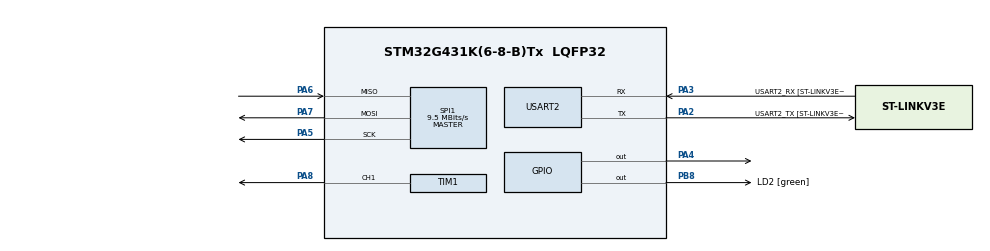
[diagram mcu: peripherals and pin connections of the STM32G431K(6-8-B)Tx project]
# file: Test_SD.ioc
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FATFS._MAX_SS=4096
FATFS._USE_LFN=1
Mcu.Family=STM32G4
Mcu.Name=STM32G431K(6-8-B)Tx
Mcu.Package=LQFP32
NVIC.PriorityGroup=NVIC_PRIORITYGROUP_4
PA13.GPIO_Label=T_SWDIO
PA13.Mode=Serial_Wire
PA13.Signal=SYS_JTMS-SWDIO
PA14.GPIO_Label=T_SWCLK
PA14.Mode=Serial_Wire
PA14.Signal=SYS_JTCK-SWCLK
PA2.GPIO_Label=USART2_TX [ST-LINKV3E_VCP_RX]
PA2.Mode=Asynchronous
PA2.Signal=USART2_TX
PA3.GPIO_Label=USART2_RX [ST-LINKV3E_VCP_TX]
PA3.Mode=Asynchronous
PA3.Signal=USART2_RX
PA4.Signal=GPIO_Output
PA5.Mode=Full_Duplex_Master
PA5.Signal=SPI1_SCK
PA6.Mode=Full_Duplex_Master
PA6.Signal=SPI1_MISO
PA7.Mode=Full_Duplex_Master
PA7.Signal=SPI1_MOSI
PA8.Signal=S_TIM1_CH1
PB3.GPIO_Label=T_SWO
PB3.Signal=SYS_JTDO-SWO
PB8-BOOT0.GPIO_Label=LD2 [green]
PB8-BOOT0.Signal=GPIO_Output
ProjectManager.HeapSize=0x200
ProjectManager.StackSize=0x400
ProjectManager.TargetToolchain=STM32CubeIDE
RCC.ADC12Freq_Value=152000000
RCC.AHBFreq_Value=152000000
RCC.APB1Freq_Value=152000000
RCC.APB1TimFreq_Value=152000000
RCC.APB2Freq_Value=152000000
RCC.APB2TimFreq_Value=152000000
RCC.CortexFreq_Value=152000000
RCC.EXTERNAL_CLOCK_VALUE=12288000
RCC.HCLKFreq_Value=152000000
RCC.HSE_VALUE=8000000
RCC.HSI48_VALUE=48000000
RCC.HSI_VALUE=16000000
RCC.LSE_VALUE=32768
RCC.PLLN=19
RCC.SYSCLKFreq_VALUE=152000000
RCC.SYSCLKSource=RCC_SYSCLKSOURCE_PLLCLK
RCC.USBFreq_Value=152000000
RCC.VCOOutputFreq_Value=304000000
SH.S_TIM1_CH1.0=TIM1_CH1,PWM Generation1 CH1
SPI1.BaudRatePrescaler=SPI_BAUDRATEPRESCALER_16
SPI1.CalculateBaudRate=9.5 MBits/s
SPI1.DataSize=SPI_DATASIZE_8BIT
SPI1.Direction=SPI_DIRECTION_2LINES
SPI1.Mode=SPI_MODE_MASTER
SPI1.VirtualType=VM_MASTER
TIM1.AutoReloadPreload=TIM_AUTORELOAD_PRELOAD_ENABLE
TIM1.Channel-PWM\ Generation1\ CH1=TIM_CHANNEL_1
TIM1.PeriodNoDither=6080-1
USART2.VirtualMode-Asynchronous=VM_ASYNC
USART2.WordLength=WORDLENGTH_8B
VP_FATFS_VS_Generic.Mode=User_defined
VP_SYS_VS_DBSignals.Mode=DisableDeadBatterySignals
board=NUCLEO-G431KB

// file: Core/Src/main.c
/* USER CODE BEGIN Header */
/**
  ******************************************************************************
  * @file           : main.c
  * @brief          : Main program body
  ******************************************************************************
  * @attention
  *
  * Copyright (c) 2022 STMicroelectronics.
  * All rights reserved.
  *
  * This software is licensed under terms that can be found in the LICENSE file
  * in the root directory of this software component.
  * If no LICENSE file comes with this software, it is provided AS-IS.
  *
  ******************************************************************************
  */
/* USER CODE END Header */
#include "main.h"
#include "app_fatfs.h"

/* USER CODE BEGIN Includes */
#include "math.h"
#include "uart_buf_g4.h"
#include "string.h"
#include "fatfs_sd.h"
#include "stdio.h"
/* USER CODE END Includes */

/* USER CODE BEGIN PD */
#define STOP_RPL            0x25
#define RESET_RPL           0x40
#define SCAN_RPL            0x20
#define FORCE_SCAN_RPL      0x21
#define GET_INFO_RPL        0x50
#define GET_HEALTH_RPL      0x52
#define GET_SAMPLERATE_RPL  0x59
#define GET_LIDAR_CONF_RPL  0x84
/*StarFlags*/
#define START_FLAG_1         0xA5
#define START_FLAG_2         0x5A
/*Tamaños del buffer*/
#define  MainBuf_SIZE 		(10*5)//13->8192 14->16384 15->32768 16->65536
#define precision 3  //precision for decimal digits
/* USER CODE END PD */

SPI_HandleTypeDef hspi1;

TIM_HandleTypeDef htim1;

UART_HandleTypeDef huart2;

/* USER CODE BEGIN PV */
// MainBuf[MainBuf_SIZE];
uint8_t ReceivingData=false;
bool AFlag=true;
//char MainBuf[MainBuf_SIZE];
char StrBufA[460*20];
//char StrBufB[128*40];
unsigned int n_points=0;
//char StrBufA[1250];
//float ValBuf[4000];
const uint8_t STOP_REQUEST[2]={START_FLAG_1,STOP_RPL};
const uint8_t RESET_REQUEST[2]={START_FLAG_1,RESET_RPL};
const uint8_t SCAN_REQUEST[2]={START_FLAG_1,SCAN_RPL};
const uint8_t SCAN_DESCRIPTOR[7]={START_FLAG_1,START_FLAG_2,0x05,0x00,0x00,0x40,0x81};
const uint8_t EXPRESS_SCAN_REQUEST[9]={START_FLAG_1,0x82,0x05,0x00,0x00,0x00,0x00,0x00,0x22};
const uint8_t EXPRESS_SCAN_DESCRIPTOR[7]={START_FLAG_1,START_FLAG_2,0x54,0x00,0x00,0x40,0x82};
const uint8_t GET_HEALTH_REQUEST[2]={START_FLAG_1,GET_HEALTH_RPL};
const uint8_t GET_HEALTH_DESCRIPTOR[7]={START_FLAG_1,START_FLAG_2,0x03,0x00,0x00,0x00,0x06};
const uint8_t GET_INFO_REQUEST[2]={START_FLAG_1,GET_INFO_RPL};
const uint8_t GET_INFO_DESCRIPTOR[7]={START_FLAG_1,START_FLAG_2,0x14,0x00,0x00,0x00,0x04};
const uint8_t GET_SAMPLERATE_REQUEST[2]={START_FLAG_1,GET_SAMPLERATE_RPL};
const uint8_t GET_SAMPLERATE_DESCRIPTOR[7]={START_FLAG_1,START_FLAG_2,0x4,0x00,0x00,0x00,0x15};
const uint8_t FORCE_SCAN_REQUEST[7]={START_FLAG_1,FORCE_SCAN_RPL};

/*Variables involucradas para la SD*/
FATFS fs;  // file system
FIL fil; // File
FILINFO fno;
FRESULT fresult;  // result
UINT br, bw;  // File read/write count

// **** capacity related ***** //
FATFS *pfs;
DWORD fre_clust;
uint32_t total, free_space;
// *************************** //
uint8_t opcion;
/* USER CODE END PV */

void SystemClock_Config(void);
static void MX_GPIO_Init(void);
static void MX_SPI1_Init(void);
static void MX_TIM1_Init(void);
static void MX_USART2_UART_Init(void);
/* USER CODE BEGIN PFP */

void setMotorDutyCycle(float duty){
	HAL_TIM_PWM_Stop(&htim1, TIM_CHANNEL_1);
	HAL_Delay(3);
	if (duty!=0){
		//El ARR tiene como valor máximo 6800@170Mhz
		//TIM1->CCR1 = (uint32_t)duty*57.6;
		TIM1->CCR1 = (uint32_t)duty*68.0;
		HAL_TIM_PWM_Start(&htim1, TIM_CHANNEL_1);
		HAL_Delay(3);
	}
}
void SEND_STOP_REQUEST(){
	//Enviamos el comando por uart
	setMotorDutyCycle(0);
	UART1buf_putn(STOP_REQUEST,2);
	//Delay >2ms para poder enviar otro request
	HAL_Delay(2);
}
void SEND_RESET_REQUEST(){
	//Enviamos el comando por uart
	UART1buf_putn(RESET_REQUEST,2);
	//Esperamos a recibir la data basura
	while(UART1buf_available()==0);
	//Delay >20ms para poder recibir toda la data basura
	HAL_Delay(50);
	//Limpiamos la data basura
	UART1buf_flushRx();
}
void SEND_GET_SAMPLERATE(){
	unsigned int temp;
	char charBuf[40];
	//Enviamos el comando por uart
	LPUART1buf_puts("Enviando comando GET_SAMPLERATE\n\r");
	UART1buf_putn(GET_SAMPLERATE_REQUEST,2);
	//Comenzamos a recibir los primeros 7 valores y verificamos si hay error
	for (int i=0;i<7;i++){
		while(UART1buf_peek()<0);
		if (GET_SAMPLERATE_DESCRIPTOR[i]!=UART1buf_getc()){
			LPUART1buf_puts((char*)"Error\n");
			//Enviar nuevamente el comando

			//Analizar si está en protección
			while(1);
		}
	}
	//Recibimos el T standard
	while(UART1buf_peek()<0);
	temp=UART1buf_getc();
	while(UART1buf_peek()<0);
	temp=(UART1buf_getc()<<8)|temp;
	//enviamos el Tstandar
	sprintf(charBuf,"Tiempo standard: %d us\n\r",temp);
	//Recibimos el T express
	LPUART1buf_puts(charBuf);
	while(UART1buf_peek()<0);
	temp=UART1buf_getc();
	while(UART1buf_peek()<0);
	temp=(UART1buf_getc()<<8)|temp;
	//enviamos el Texpress
	sprintf(charBuf,"Tiempo express: %d us\n\r",temp);
	LPUART1buf_puts(charBuf);
	HAL_Delay(50);
}
void SEND_GET_HEALTH(){
	unsigned int temp;
	char charBuf[40];
	//Enviamos el comando por uart
	LPUART1buf_puts("Enviando comando GET_HEALTH\n\r");
	UART1buf_putn(GET_HEALTH_REQUEST,2);
	//Comenzamos a recibir los primeros 7 valores y verificamos si hay error
	for (int i=0;i<7;i++){
		while(UART1buf_peek()<0);
		if (GET_HEALTH_DESCRIPTOR[i]!=UART1buf_getc()){
			LPUART1buf_puts((char*)"Error\n");
			//Enviar nuevamente el comando

			//Analizar si está en protección
			while(1);
		}
	}
	//Recibimos el status
	while(UART1buf_peek()<0);
	temp=UART1buf_getc();
	if (temp==0){
		LPUART1buf_puts("Todo en orden!\n\r");
		while(UART1buf_peek()<0);
		UART1buf_getc();
		while(UART1buf_peek()<0);
		UART1buf_getc();
	}
	//Warning
	else if (temp==1){
		LPUART1buf_puts("Advertencia: ");
		while(UART1buf_peek()<0);
		temp=UART1buf_getc();
		while(UART1buf_peek()<0);
		temp=(UART1buf_getc()<<8)|temp;
		sprintf(charBuf,"code %d\n\r",temp);
		LPUART1buf_puts(charBuf);

	}
	//
	else{
		LPUART1buf_puts("Error: ");
		while(UART1buf_peek()<0);
		temp=UART1buf_getc();
		while(UART1buf_peek()<0);
		temp=(UART1buf_getc()<<8)|temp;
		sprintf(charBuf,"code %d\n\r",temp);
		LPUART1buf_puts(charBuf);
	}
	HAL_Delay(50);
}
void SEND_GET_LIDAR_CONF(){
	/*Realizaremos varios request*/
	uint8_t charBuf[40];
	/***************************/
	//Enviamos el comando por uart
	LPUART1buf_puts("RPLIDAR_CONF_SCAN_MODE_TYPICAL\n\r");
	charBuf[0]=START_FLAG_1;
	charBuf[1]=0x84;
	charBuf[2]=0x04;//tamaño
	charBuf[3]=0x00;//type
	charBuf[4]=0x00;//type
	charBuf[5]=0x00;//type
	charBuf[6]=0x7C;//type
	charBuf[7]=0x59;//checksum
	UART1buf_putn(charBuf,8);
	//Definimos el descriptor y el tipo
	charBuf[0]=START_FLAG_1;
	charBuf[1]=START_FLAG_2;
	charBuf[2]=0x04;//tamaño del request
	charBuf[3]=0x00;
	charBuf[4]=0x00;
	charBuf[5]=0x00;
	charBuf[6]=0x20;
	charBuf[7]=0x00;//type
	charBuf[8]=0x00;//type
	charBuf[9]=0x00;//type
	charBuf[10]=0x7C;//type

	//Comenzamos a recibir los primeros 7+4 valores y verificamos si hay error
	for (int i=0;i<11;i++){
		while(UART1buf_peek()<0);
		if (charBuf[i]!=UART1buf_getc()){
			LPUART1buf_puts((char*)"Error 0\n");
			//Enviar nuevamente el comando

			//Analizar si está en protección
			while(1);
		}
	}
	LPUART1buf_puts("No value received\n\r");
	//while(UART1buf_peek()<0);
	//temp=UART1buf_getc();
	//while(UART1buf_peek()<0);
	//temp=(UART1buf_getc()<<8)|temp;
	//sprintf(charBuf,"ID: %d \n\r",temp);
	//LPUART1buf_puts(charBuf);
	HAL_Delay(50);
	/***************************/
	//Enviamos el comando por uart
	LPUART1buf_puts("RPLIDAR_CONF_SCAN_MODE_COUNT\n\r");
	charBuf[0]=START_FLAG_1;
	charBuf[1]=0x84;
	charBuf[2]=0x04;//tamaño
	charBuf[3]=0x00;//type
	charBuf[4]=0x00;//type
	charBuf[5]=0x00;//type
	charBuf[6]=0x70;//type
	charBuf[7]=0x55;//checksum
	UART1buf_putn(charBuf,8);
	//Definimos el descriptor y el tipo
	charBuf[0]=START_FLAG_1;
	charBuf[1]=START_FLAG_2;
	charBuf[2]=0x04;//tamaño response
	charBuf[3]=0x00;
	charBuf[4]=0x00;
	charBuf[5]=0x00;
	charBuf[6]=0x20;
	charBuf[7]=0x00;//type
	charBuf[8]=0x00;//type
	charBuf[9]=0x00;//type
	charBuf[10]=0x70;//type

	//Comenzamos a recibir los primeros 7+4 valores y verificamos si hay error
	for (int i=0;i<11;i++){
		while(UART1buf_peek()<0);
		if (charBuf[i]!=UART1buf_getc()){
			LPUART1buf_puts((char*)"Error 1\n");
			//Enviar nuevamente el comando

			//Analizar si está en protección
			while(1);
		}
	}
	LPUART1buf_puts("No value received\n\r");
	//LPUART1buf_puts("N. modos: 0");
	//while(UART1buf_peek()<0);
	//temp=UART1buf_getc();
	//while(UART1buf_peek()<0);
	//temp=(UART1buf_getc()<<8)|temp;
	//sprintf(charBuf,"%d\n\r",temp-1);
	//LPUART1buf_puts(charBuf);
	HAL_Delay(50);
	/***************************/
	//Enviamos el comando por uart
	LPUART1buf_puts("RPLIDAR_CONF_SCAN_MODE_US_PER_SAMPLE\n\r");
	charBuf[0]=START_FLAG_1;
	charBuf[1]=0x84;
	charBuf[2]=0x06;//tamaño
	charBuf[3]=0x00;//type
	charBuf[4]=0x00;//type
	charBuf[5]=0x00;//type
	charBuf[6]=0x71;//type
	charBuf[7]=0x00;//payload
	charBuf[8]=0x00;//payload
	charBuf[9]=0x56;//checksum
	UART1buf_putn(charBuf,10);
	//Definimos el descriptor y el tipo
	charBuf[0]=START_FLAG_1;
	charBuf[1]=START_FLAG_2;
	charBuf[2]=0x04;//tamaño del request
	charBuf[3]=0x00;
	charBuf[4]=0x00;
	charBuf[5]=0x00;
	charBuf[6]=0x20;
	charBuf[7]=0x00;//type
	charBuf[8]=0x00;//type
	charBuf[9]=0x00;//type
	charBuf[10]=0x71;//type

	//Comenzamos a recibir los primeros 7+4 valores y verificamos si hay error
	for (int i=0;i<11;i++){
		while(UART1buf_peek()<0);
		if (charBuf[i]!=UART1buf_getc()){
			LPUART1buf_puts((char*)"Error 2\n");
			//Enviar nuevamente el comando

			//Analizar si está en protección
			while(1);
		}
	}
	LPUART1buf_puts("No value received\n\r...\n\r");
	//while(UART1buf_peek()<0);
	//temp=UART1buf_getc();
	//while(UART1buf_peek()<0);
	//temp=(UART1buf_getc()<<8)|temp;
	//while(UART1buf_peek()<0);
	//temp=(UART1buf_getc()<<8)|temp;
	//while(UART1buf_peek()<0);
	//temp=(UART1buf_getc()<<8)|temp;
	//sprintf(charBuf,"%d \n\r",temp);
	//LPUART1buf_puts(charBuf);
	HAL_Delay(50);
}
uint8_t  BinToAsc(uint8_t  BinValue)
{
	//tomamos los 4 bits menos significativos
    BinValue &= 0x0F;
    //hacemos la conversion
    if(BinValue > 9) BinValue += 7;
    return(BinValue + '0');
}
void SEND_GET_INFO(){
	unsigned int temp,temp_aux_1;
	char charBuf[40];
	//Enviamos el comando por uart
	LPUART1buf_puts("Enviando comando GET_INFO\n\r");
	UART1buf_putn(GET_INFO_REQUEST,2);
	//Comenzamos a recibir los primeros 7 valores y verificamos si hay error
	for (int i=0;i<7;i++){
		while(UART1buf_peek()<0);
		if (GET_INFO_DESCRIPTOR[i]!=UART1buf_getc()){
			LPUART1buf_puts((char*)"Error\n");
			//Enviar nuevamente el comando

			//Analizar si está en protección
			while(1);
		}
	}
	//Recibimos el modelo
	while(UART1buf_peek()<0);
	temp=UART1buf_getc();
	sprintf(charBuf,"modelo: %d\n\r",temp);
	LPUART1buf_puts(charBuf);
	while(UART1buf_peek()<0);
	temp_aux_1=UART1buf_getc();
	while(UART1buf_peek()<0);
	temp=UART1buf_getc();
	sprintf(charBuf,"firmware: %d.%d\n\r",temp,temp_aux_1);
	LPUART1buf_puts(charBuf);
	while(UART1buf_peek()<0);
	temp=UART1buf_getc();
	sprintf(charBuf,"hardware: %d\n\r",temp);
	LPUART1buf_puts(charBuf);
	LPUART1buf_puts("Serial number: ");
	for (int z=0;z<16;z++){
		while(UART1buf_peek()<0);
		temp=UART1buf_getc();
		charBuf[z*2+0]=BinToAsc((temp>>4));
		charBuf[z*2+1]=BinToAsc(temp);
	}
	charBuf[32]='\0';
	LPUART1buf_puts(charBuf);
	LPUART1buf_puts("\n\r");
	HAL_Delay(50);
}
//
//void SEND_EXPRESS_SCAN(){
//	uint8_t sync,ChkSum_lidar,ChkSum;
//	uint8_t dtheta_1,dtheta_2;
//	uint16_t start_angle_q6,dist_1,dist_2;
//	//bool S;
//	float wi,wip1,angle,distance;//x,y;
//	//Ahora encendemos el motor
//	setMotorDutyCycle(60);
//	UART1buf_flushRx();
//	//Enviamos el comando por uart
//	UART1buf_putn(EXPRESS_SCAN_REQUEST,9);
//	//Comenzamos a recibir los primeros 7 valores y verificamos si hay error
//	for (int i=0;i<7;i++){
//		while(UART1buf_peek()<0);
//		if (EXPRESS_SCAN_DESCRIPTOR[i]!=UART1buf_getc()){
//			LPUART1buf_puts((char*)"Error EXPRESS SCAN\n");
//			//Enviar nuevamente el comando
//
//			//Analizar si está en protección
//			while(1);
//		}
//	}
//	//Procedemos a decodificar un paquete de 32 muestras del LIDAR
//	ChkSum=0;
//	while(UART1buf_peek()<0);
//	ChkSum^=UART1buf_peek();
//	sync=(UART1buf_peek()&0xF0);
//	ChkSum_lidar=UART1buf_getc()&0x0F;
//	while(UART1buf_peek()<0);
//	ChkSum^=UART1buf_peek();
//	sync|=(UART1buf_peek()>>4);
//	ChkSum_lidar|=(UART1buf_getc()<<4);
//	while(UART1buf_peek()<0);
//	ChkSum^=UART1buf_peek();
//	start_angle_q6=UART1buf_getc();
//	while(UART1buf_peek()<0);
//	ChkSum^=UART1buf_peek();
//	S=UART1buf_peek()>>7;
//	start_angle_q6|=(UART1buf_getc()<<8)&0x7F;
//	wi=(float)start_angle_q6/64.0;
//	//Debemos analizar la siguiente banderaif (S)
//	if (sync!=0xA5){
//		//Procedemos a recibir las 16 cabinas copn 32 muestras
//		for (int k=0;k<16;k++){
//			while(UART1buf_peek()<0);
//			ChkSum^=UART1buf_peek();
//			dtheta_1=((UART1buf_peek())<<4);
//			dist_1=(UART1buf_getc()>>2);
//			while(UART1buf_peek()<0);
//			ChkSum^=UART1buf_peek();
//			dist_1|=(UART1buf_getc()>>6);
//			while(UART1buf_peek()<0);
//			ChkSum^=UART1buf_peek();
//			dtheta_2=((UART1buf_peek())<<4);
//			dist_2=(UART1buf_getc()>>2);
//			while(UART1buf_peek()<0);
//			ChkSum^=UART1buf_peek();
//			dist_2|=(UART1buf_getc()>>6);
//			while(UART1buf_peek()<0);
//			ChkSum^=UART1buf_peek();
//			dtheta_1|=UART1buf_peek()&0x0F;
//			dtheta_2|=(UART1buf_getc()>>4);
//			ValBuf[k*4+0]=dtheta_1;
//			ValBuf[k*4+1]=dist_1;
//			ValBuf[k*4+2]=dtheta_2;
//			ValBuf[k*4+3]=dist_2;
//		}
//		//Chequeamos si el Checksum es correcto.
//
//	}else{
//		//error comunicacion
//		while(1);
//	}
//	//Para poder procesar necesitamos el ángulo del siguiente estado wi+1
//	while(1){
//		ChkSum=0;
//		while(UART1buf_peek()<0);
//		ChkSum^=UART1buf_peek();
//		sync=(UART1buf_peek()&0xF0);
//		ChkSum_lidar=UART1buf_getc()&0x0F;
//		while(UART1buf_peek()<0);
//		ChkSum^=UART1buf_peek();
//		sync|=(UART1buf_peek()>>4);
//		ChkSum_lidar|=(UART1buf_getc()<<4);
//		while(UART1buf_peek()<0);
//		ChkSum^=UART1buf_peek();
//		start_angle_q6=UART1buf_getc();
//		while(UART1buf_peek()<0);
//		ChkSum^=UART1buf_peek();
//		S=UART1buf_peek()>>7;
//		start_angle_q6|=(UART1buf_getc()<<8)&0x7F;
//		wip1=(float)start_angle_q6/64.0;
//		//Debemos analizar sync,ChkSum y S
//
//		//...Continuar aqui. Falta decodificar la data con el AngleDiff
//
//		//if (butonpressed){
//		//	break
//		//}
//	}
//
//
//
//
//}
//
/***************************************************************/
/** @brief Proponemos usar un buffer que almacene los valores
 * float de x e y. Para luego, de tener un SCAN. Enviar los datos
 * a la SD. El envío a la tarjeta SD será cada 100 ms aprox, es
 * decir. Luego de completar un SCAN (que se verifica con el S
 * flag), enviamos archivos.
 *
 *
 */
//oid SAVE_DATA_bufdouble(){
//	//Define variables
//	float angle,distance,x,y;
//	uint8_t C,S,first_point_set;
//	unsigned int temp,index=0,wrong_points=0;
//	uint8_t chars_buf[40];
//	//Primero para crear el archivo en donde almacenaremos la data, debemos eliminar el existente
//	f_unlink("/data.csv");
//	//Ahora lo creamos
//	while(f_open(&fil, "data.csv", FA_OPEN_ALWAYS | FA_READ | FA_WRITE)!= FR_OK);
//	//Escribimos la primera línea
//	while(f_write(&fil, "Data a almacenar [x,y]:\n",sizeof("Data a almacenar [x,y]:\n") , &bw)!= FR_OK);
//	//Ahora encendemos el motor
//	setMotorDutyCycle(60);
//	//HAL_GPIO_TogglePin(LD2_GPIO_Port, LD2_Pin);
//	HAL_Delay(70);
//	//HAL_GPIO_TogglePin(LD2_GPIO_Port, LD2_Pin);
//	//Limpiamos el buffer de Recepción
//	UART1buf_flushRx();
//	//Enviamos el comando por uart
//	UART1buf_putn(SCAN_REQUEST,2);
//	//Comenzamos a recibir los primeros 7 valores y verificamos si hay error
//	for (int i=0;i<7;i++){
//		while(UART1buf_peek()<0);
//		if (SCAN_DESCRIPTOR[i]!=UART1buf_getc()){
//			LPUART1buf_puts((char*)"Error\nA5-5A-05-00-00-40-81\n\r");
//			//Enviar nuevamente el comando
//
//			//Analizar si está en protección
//			while(1);
//		}
//	}
//	//Procedemos a recibir la data del RPLIDAR hasta obtener el punto de inicio de SCAN y guardamos en SD
//	while(1){
//		while(UART1buf_peek()<0);
//		/****Decodificamos la bandera Flag****/
//		S=UART1buf_getc()&0x03;
//		if (S==0x01){
//			/****Decodificamos el checkbit****/
//			while(UART1buf_peek()<0);
//			chars_buf[1]=
//			C=UART1buf_peek()&0x01;
//			if (C){
//				/****Decodificamos el Angle****/
//				//Desplazamos los bits
//				temp=(UART1buf_getc()>>1);
//				temp|=(UART1buf_getc()<<7);
//				angle=(float)temp/64.0;
//				angle=angle*M_PI/180.0;
//				/****Decodificamos la distancia****/
//				//Desplazamos los bits
//				temp=UART1buf_getc();
//				temp|=(UART1buf_getc()<<8);
//				distance=(float)temp/4.0;
//				///Procedemos a convertir en coordenadas cartesianas
//				ValBuf[index*2+0]=distance*cosf(angle+M_PI_2);
//				ValBuf[index*2+1]=distance*sinf(angle+M_PI_2);
//				index++;
//				first_point_set=false;
//				break;
//			}
//			else{
//				//No sirve dato
//				while(UART1buf_peek()<0);
//				UART1buf_getc();
//				while(UART1buf_peek()<0);
//				UART1buf_getc();
//				while(UART1buf_peek()<0);
//				UART1buf_getc();
//				while(UART1buf_peek()<0);
//				UART1buf_getc();
//			}
//		}else{
//			//No sirve dato
//			for (int i=0;i<4;i++){
//				while(UART1buf_peek()<0);
//				UART1buf_getc();
//			}
//		}
//	}
//	while(1){
//		while(UART1buf_peek()<0);
//		/****Decodificamos la bandera Flag****/
//		S=UART1buf_getc()&0x03;
//		if ((S==(0x01))||(S==(0x02))){
//			if (S==(0x01)){
//				first_point_set=true;
//			}
//			/****Decodificamos el checkbit****/
//			while(UART1buf_peek()<0);
//
//			if (UART1buf_peek()&0x01){
//				/****Decodificamos el Angle****/
//				//Desplazamos los bits
//				temp=(UART1buf_getc()>>1);
//				temp|=(UART1buf_getc()<<7);
//				angle=(float)temp/64.0;
//				angle=angle*M_PI/180.0;
//				/****Decodificamos la distancia****/
//				//Desplazamos los bits
//				temp=UART1buf_getc();
//				temp|=(UART1buf_getc()<<8);
//				distance=(float)temp/4.0;
//				///Procedemos a convertir en coordenadas cartesianas
//				ValBuf[index*2+0]=distance*cosf(angle+M_PI_2);
//				ValBuf[index*2+1]=distance*sinf(angle+M_PI_2);
//				index++;
//			}
//			else{
//				//Dato errado
//				UART1buf_getc();
//				while(UART1buf_peek()<0);
//				UART1buf_getc();
//				while(UART1buf_peek()<0);
//				UART1buf_getc();
//				while(UART1buf_peek()<0);
//				UART1buf_getc();
//				wrong_points++;
//			}
//		}else{
//			//Dato errado
//			for (int i=0;i<5;i++){
//				while(UART1buf_peek()<0);
//				UART1buf_getc();
//			}
//			wrong_points++;
//		}
//		//Si terminamos un SCAN procesamos y enviamos a la SD
//		if (first_point_set){
//			first_point_set=false;
//			x=ValBuf[index*2-2];
//			y=ValBuf[index*2-1];
//			//escribimos en la SD
//			for(int z=0;z<index;z++){
//				sprintf(chars_buf,"%.3f,%.3f\n",ValBuf[z*2+0],ValBuf[z*2+0]);
//				while(f_lseek(&fil, f_size(&fil))!= FR_OK);
//				f_puts(chars_buf, &fil);
//			}
//			for(int z=0;z<wrong_points;z++){
//				while(f_lseek(&fil, f_size(&fil))!= FR_OK);
//				f_puts("NaN,NaN\n", &fil);
//			}
//			wrong_points=0;
//			ValBuf[0]=x;
//			ValBuf[1]=y;
//			index=1;
//			//read aditional data to sync
//			for(int z=0;z<7*5;z++){
//				while(UART1buf_peek()<0);
//				UART1buf_getc();
//			}
//		}
//		//Verificamos estado del butón
//		if (HAL_GPIO_ReadPin(GPIOB, GPIO_PIN_4)){
//			HAL_Delay(50);
//			//Cerramos el archivo
//			f_close(&fil);
//			//Salimos del while
//			break;
//		}
//	}
//	///* Unmount SDCARD */
//	while(f_mount(NULL, "/", 1)!= FR_OK);
//	LPUART1buf_puts ("SD CARD UNMOUNTED successfully, puedes retirar la tarjeta\n\r");
//	//Mandamos el comando de STOP
//	UART1buf_putn(STOP_REQUEST, 2);
//	//Detenemos el motor
//	setMotorDutyCycle(0);
//	HAL_Delay(2);
//	//Borramos data del buffer
//	UART1buf_flushRx();
//	//Enviamos "fin de SAVE_SCAN_DATA"
//	LPUART1buf_puts ("Fin de la operación\n\r");
//
//
//
///************************************************************/
void float_to_char(float f, char *p) {
	int a,b,c,k,l=0,m,i=0;
	// check for negetive float
	if(f<0.0)
	{
		p[i++]='-';
		f*=-1;
	}
	a=f;	// extracting whole number
	f-=a;	// extracting decimal part
	k = precision;
	// number of digits in whole number
	while(k>-1)
	{
		l = pow(10,k);
		m = a/l;
		if(m>0)
		{
			break;
		}
	k--;
	}
	// number of digits in whole number are k+1
	/*
	extracting most significant digit i.e. right most digit , and concatenating to string
	obtained as quotient by dividing number by 10^k where k = (number of digit -1)
	*/
	for(l=k+1;l>0;l--)
	{
		b = pow(10,l-1);
		c = a/b;
		p[i++]=c+48;
		a%=b;
	}
	p[i++] = '.';
	/* extracting decimal digits till precision */
	for(l=0;l<precision;l++)
	{
		f*=10.0;
		b = f;
		p[i++]=b+48;
		f-=b;
	}
	p[i]='\0';
}
void SAVE_SCAN_DATA(){
	if ((opcion!='1')&&(opcion!='2')&&(opcion!='3')&&(opcion!='0')&&(opcion!='4')){
		return;
	}
	//Define variables
	uint16_t temp;
	float angle,distance;
	float x,y;
	unsigned int n_bytes=0;
	char chars_buf[24];
	uint8_t MainBuf[10];
	StrBufA[0]='\0';
	//Primero para crear el archivo en donde almacenaremos la data, debemos eliminar el existente
	f_unlink("/test.csv");
	//Ahora lo creamos
	while(f_open(&fil, "test.csv", FA_OPEN_ALWAYS | FA_READ | FA_WRITE)!= FR_OK);
	//Escribimos la primera línea
	while(f_write(&fil, "Data a almacenar [x,y]:\n",sizeof("Data a almacenar [x,y]:\n") , &bw)!= FR_OK);
	//Ahora encendemos el motor
	setMotorDutyCycle(60);
	HAL_Delay(1000);
	//Limpiamos el buffer de Recepción
	UART1buf_flushRx();
	//Enviamos el comando por uart
	UART1buf_putn(SCAN_REQUEST,2);
	//Comenzamos a recibir los primeros 7 valores y verificamos si hay error
	for (int i=0;i<7;i++){
		//while(!UART1buf_available());
		while(UART1buf_peek()<0);
		if (SCAN_DESCRIPTOR[i]!=UART1buf_getc()){
			LPUART1buf_puts((char*)"Error\nA5-5A-05-00-00-40-81\n\r");
			//Enviar nuevamente el comando

			//Analizar si está en protección
			while(1);
		}
	}
	ReceivingData=true;
/********************************************************************/
	while(opcion=='0'){//usando peek
		if (!(UART1buf_peek()<0)){
			//Hay dato,lo guardamos
			HAL_GPIO_WritePin(LD2_GPIO_Port, LD2_Pin,0);
			MainBuf[n_points]=UART1buf_getc();
			n_points++;
			f_lseek(&fil, f_size(&fil));
		}
		if (n_points>4){
			//Tenemos ya 5 datos para procesar
			n_points=0;
			if((((MainBuf[0]&0x03)==1)||((MainBuf[0]&0x03)==2))&&((MainBuf[1]&0x01)==1)){
				HAL_GPIO_WritePin(LD2_GPIO_Port, LD2_Pin,1);
				temp=(MainBuf[1]>>1)&0x7F;
				temp|=(MainBuf[2]<<7);
				angle=(float)temp/64.0;
				//angle=temp;
				angle=angle*M_PI/180.0;
				// ******Decodificamos la distancia****  //
				//Desplazamos los bits
				temp=MainBuf[3];
				temp|=(MainBuf[4]<<8);
				distance=(float)temp/4.0;
				//distance=temp;
				//Procedemos a convertir en coordenadas cartesianas
				x=distance*cosf(angle+M_PI_2);
				y=distance*sinf(angle+M_PI_2);
				//Realizamos la conversión float a string
				sprintf(chars_buf,"%.3f,%.3f\n",x,y);
				/*float_to_char(x,chars_buf);
				StrBufA[0]='\0';
				strcat(StrBufA,chars_buf);
				strcat(StrBufA,",");
				float_to_char(y,chars_buf);
				strcat(StrBufA,chars_buf);
				strcat(StrBufA,"\n");*/
				HAL_GPIO_WritePin(LD2_GPIO_Port, LD2_Pin,0);
			}else{
				StrBufA[0]='I';
				StrBufA[1]='n';
				StrBufA[2]='f';
				StrBufA[3]=',';
				StrBufA[4]='I';
				StrBufA[5]='n';
				StrBufA[6]='f';
				StrBufA[7]='\n';
			}
		}

		if (LPUART1buf_peek()>0){
			LPUART1buf_puts("Deteniendo SCAN\n\r");
			//Cerramos el archivo
			f_close(&fil);
			ReceivingData=false;
			//Salimos del while
			break;

		}

	}
	while(opcion=='1'){//Solo vemos el punto de inicio de SCAN
		if (!(UART1buf_peek()<0)){
			//Hay dato,lo guardamos
			HAL_GPIO_WritePin(LD2_GPIO_Port, LD2_Pin,0);
			MainBuf[n_points]=UART1buf_getc();
			n_points++;
		}
		if (n_points>4){
			//Tenemos ya 5 datos para procesar
			n_points=0;
			if (((MainBuf[0]&0x03)==1)&&((MainBuf[1]&0x01)==1)){
				HAL_GPIO_WritePin(LD2_GPIO_Port, LD2_Pin,1);
				temp=(MainBuf[1]>>1)&0x7F;
				temp|=(MainBuf[2]<<7);
				angle=(float)temp/64.0;
				//angle=temp;
				angle=angle*M_PI/180.0;
				// ******Decodificamos la distancia****  //
				//Desplazamos los bits
				temp=MainBuf[3];
				temp|=(MainBuf[4]<<8);
				distance=(float)temp/4.0;
				//distance=temp;
				//Procedemos a convertir en coordenadas cartesianas
				x=distance*cosf(angle+M_PI_2);
				y=distance*sinf(angle+M_PI_2);
				//Realizamos la conversión float a string
				sprintf(chars_buf,"%.3f,%.3f\n",x,y);
				/*
				float_to_char(x,chars_buf);
				StrBufA[0]='\0';
				strcat(StrBufA,chars_buf);
				strcat(StrBufA,",");
				float_to_char(y,chars_buf);
				strcat(StrBufA,chars_buf);
				strcat(StrBufA,"\n");*/
				HAL_GPIO_WritePin(LD2_GPIO_Port, LD2_Pin,0);
			}
		}
		if (LPUART1buf_peek()>0){
			LPUART1buf_puts("Deteniendo SCAN\n\r");
			//Cerramos el archivo
			f_close(&fil);
			//Salimos del while
			break;
		}
	}
	//TxState=TRANSFER_COMPLETE;
	while(opcion=='2'){//Recibe y guarda
		if (!(UART1buf_peek()<0)){
			//Hay dato,lo guardamos
			//HAL_GPIO_WritePin(LD2_GPIO_Port, LD2_Pin,1);
			MainBuf[n_bytes]=UART1buf_getc();
			n_bytes++;
		}
		if (n_bytes>4){
			//Tenemos ya 5 datos para procesar
			n_bytes=0;
			/*if((n_points&0x00000007)==7){
				//no leemos
				chars_buf[0]='0';
				chars_buf[1]=',';
				chars_buf[2]='0';
				chars_buf[3]='\n';
				chars_buf[4]='\0';
			}else */
			if((((MainBuf[0]&0x03)==1)||((MainBuf[0]&0x03)==2))&&((MainBuf[1]&0x01)==1)){
				HAL_GPIO_WritePin(LD2_GPIO_Port, LD2_Pin,1);
				temp=(MainBuf[1]>>1)&0x7F;
				temp|=(MainBuf[2]<<7);
				angle=(float)temp/64.0;
				angle=angle*M_PI/180.0;
				// ******Decodificamos la distancia****  //
				//Desplazamos los bits
				temp=MainBuf[3];
				temp|=(MainBuf[4]<<8);
				distance=(float)temp/4.0;
				//distance=temp;
				//Procedemos a convertir en coordenadas cartesianas
				x=distance*cosf(angle+M_PI_2);
				y=distance*sinf(angle+M_PI_2);
				//Realizamos la conversión float a string
				sprintf(chars_buf,"%.2f,%.2f\n",x,y);
				/*float_to_char(x,chars_buf);
				StrBufA[0]='\0';
				strcat(StrBufA,chars_buf);
				strcat(StrBufA,",");
				float_to_char(y,chars_buf);
				strcat(StrBufA,chars_buf);
				strcat(StrBufA,"\n");*/
				HAL_GPIO_WritePin(LD2_GPIO_Port, LD2_Pin,0);
			}else{
				chars_buf[0]='I';
				chars_buf[1]='n';
				chars_buf[2]='f';
				chars_buf[3]=',';
				chars_buf[4]='I';
				chars_buf[5]='n';
				chars_buf[6]='f';
				chars_buf[7]='\n';
				chars_buf[8]='\0';
			}
			n_points++;
			//if(AFlag){
				strcat(StrBufA,chars_buf);
			//}else{
			//	strcat(StrBufB,chars_buf);
			//}
			//HAL_GPIO_WritePin(LD2_GPIO_Port, LD2_Pin,1);
		}
		//&&(TxState==TRANSFER_COMPLETE)
		if((n_points>64)){
			//Podemos escribir en la SD
			//HAL_GPIO_WritePin(LD2_GPIO_Port, LD2_Pin,1);
			//TxState=TRANSFER_WAIT;
			//f_puts(StrBufA, &fil);
			//if(AFlag){
				//AFlag=0;
				f_write(&fil, StrBufA, strlen(StrBufA),&bw);
				StrBufA[0]='\0';
			//}else{
				//AFlag=1;
				//f_write(&fil, StrBufB, strlen(StrBufB),&bw);
				//StrBufB[0]='\0';
			//}
			//while(TxState==TRANSFER_WAIT);
			n_points=0;
			//HAL_GPIO_WritePin(LD2_GPIO_Port, LD2_Pin,0);
		}
		if (!(LPUART1buf_peek()<0)){
			LPUART1buf_puts("Deteniendo SCAN\n\r");
			//Cerramos el archivo
			f_close(&fil);
			//Salimos del while
			break;
		}
	}
/**************************************************************/
	ReceivingData=false;
	LPUART1buf_getc();
	//Mandamos el comando de STOP
	UART1buf_putn(STOP_REQUEST, 2);
	//Detenemos el motor
	setMotorDutyCycle(0);
	HAL_Delay(2);
	//Borramos data del buffer
	UART1buf_flushRx();
	//Enviamos "fin de SAVE_SCAN_DATA"
	LPUART1buf_puts ("Fin de la operación\n\r");
}

/* USER CODE END PFP */

int main(void)
{

  /* MCU Configuration--------------------------------------------------------*/

  /* Reset of all peripherals, Initializes the Flash interface and the Systick. */
  HAL_Init();

  /* Configure the system clock */
  SystemClock_Config();

  /* Initialize all configured peripherals */
  MX_GPIO_Init();
  MX_SPI1_Init();
  if (MX_FATFS_Init() != APP_OK) {
    Error_Handler();
  }
  MX_TIM1_Init();
  MX_USART2_UART_Init();
  /* USER CODE BEGIN 2 */
  char buffer[64];
  //Inicializamos los UARTs
  LPUART1buf_init(115200,SERIAL_8N1,0);
  UART1buf_init(256000,SERIAL_8N1,0);

  //Mount SD card
  LPUART1buf_puts("Intentando mounted SD CARD...\n\r");
  HAL_Delay (500);
  //fresult=f_mount(&fs, "/", 1);
  while (f_mount(&fs,"/", 1) != FR_OK);
  LPUART1buf_puts("SD CARD mounted successfully...\n\r");
  /*************** Card capacity details ********************/
  /* Check free space */
  //fresult=f_getfree("", &fre_clust, &pfs);
  while(f_getfree("", &fre_clust, &pfs)!= FR_OK);
  total = (uint32_t)((pfs->n_fatent - 2) * pfs->csize * 0.5);
  sprintf (buffer,"SD CARD Total Size: \t%lu\n\r",total);
  LPUART1buf_puts(buffer);
  free_space = (uint32_t)(fre_clust * pfs->csize * 0.5);
  sprintf (buffer, "SD CARD Free Space: \t%lu\n\r",free_space);
  LPUART1buf_puts(buffer);
  //Enviamos el comando de RESET
  SEND_RESET_REQUEST();//DESCOMENTAR LUEGO DE TEMRINAR CON EL SD
  /* USER CODE END 2 */

  /* Infinite loop */
  /* USER CODE BEGIN WHILE */
  while (1)
  {
	  //SEND_GET_SAMPLERATE();
	  SEND_GET_HEALTH();
	  //SEND_GET_LIDAR_CONF();
	  SEND_GET_INFO();
	  //SEND_EXPRESS_SCAN();

	  //Esperamos a que se presione el Boton
	  LPUART1buf_puts((char*)"Iniciamos:\n\r");
	  LPUART1buf_puts((char*)"0: usando peek\n\r");
	  LPUART1buf_puts((char*)"1: Vemos solo puntos de inicio\n\r");
	  LPUART1buf_puts((char*)"2: Recibe y guarda\n\r");
	  LPUART1buf_puts((char*)"3: Codigo Lalo\n\r");
	  while(LPUART1buf_peek()<0);
	  opcion=LPUART1buf_getc();
	  //LPUART1buf_flushRx();
	  LPUART1buf_puts((char*)"Mandamos SCAN request:\n\r");
	  //SAVE_DATA_bufdouble();
	  SAVE_SCAN_DATA();

	  LPUART1buf_puts((char*)"Desmount SD?:\n\r");
	  while(LPUART1buf_peek()<0);
	  opcion=LPUART1buf_getc();
	  if(opcion=='Y')
	  {/* Unmount SDCARD */
		while(f_mount(NULL, "/", 1)!= FR_OK);
		LPUART1buf_puts ("SD CARD UNMOUNTED successfully, puedes retirar la tarjeta\n\r");
		while(1);
	  }
	  //setMotorDutyCycle(60);
	  //while(1);
    /* USER CODE END WHILE */

  }
}

void SystemClock_Config(void)
{
  RCC_OscInitTypeDef RCC_OscInitStruct = {0};
  RCC_ClkInitTypeDef RCC_ClkInitStruct = {0};

  /** Configure the main internal regulator output voltage
  */
  HAL_PWREx_ControlVoltageScaling(PWR_REGULATOR_VOLTAGE_SCALE1_BOOST);
  /** Initializes the RCC Oscillators according to the specified parameters
  * in the RCC_OscInitTypeDef structure.
  */
  RCC_OscInitStruct.OscillatorType = RCC_OSCILLATORTYPE_HSI;
  RCC_OscInitStruct.HSIState = RCC_HSI_ON;
  RCC_OscInitStruct.HSICalibrationValue = RCC_HSICALIBRATION_DEFAULT;
  RCC_OscInitStruct.PLL.PLLState = RCC_PLL_ON;
  RCC_OscInitStruct.PLL.PLLSource = RCC_PLLSOURCE_HSI;
  RCC_OscInitStruct.PLL.PLLM = RCC_PLLM_DIV4;
  RCC_OscInitStruct.PLL.PLLN = 85;
  RCC_OscInitStruct.PLL.PLLP = RCC_PLLP_DIV2;
  RCC_OscInitStruct.PLL.PLLQ = RCC_PLLQ_DIV2;
  RCC_OscInitStruct.PLL.PLLR = RCC_PLLR_DIV2;
  if (HAL_RCC_OscConfig(&RCC_OscInitStruct) != HAL_OK)
  {
    Error_Handler();
  }
  /** Initializes the CPU, AHB and APB buses clocks
  */
  RCC_ClkInitStruct.ClockType = RCC_CLOCKTYPE_HCLK|RCC_CLOCKTYPE_SYSCLK
                              |RCC_CLOCKTYPE_PCLK1|RCC_CLOCKTYPE_PCLK2;
  RCC_ClkInitStruct.SYSCLKSource = RCC_SYSCLKSOURCE_PLLCLK;
  RCC_ClkInitStruct.AHBCLKDivider = RCC_SYSCLK_DIV1;
  RCC_ClkInitStruct.APB1CLKDivider = RCC_HCLK_DIV1;
  RCC_ClkInitStruct.APB2CLKDivider = RCC_HCLK_DIV1;

  if (HAL_RCC_ClockConfig(&RCC_ClkInitStruct, FLASH_LATENCY_4) != HAL_OK)
  {
    Error_Handler();
  }
}

static void MX_SPI1_Init(void)
{

  /* SPI1 parameter configuration*/
  hspi1.Instance = SPI1;
  hspi1.Init.Mode = SPI_MODE_MASTER;
  hspi1.Init.Direction = SPI_DIRECTION_2LINES;
  hspi1.Init.DataSize = SPI_DATASIZE_8BIT;
  hspi1.Init.CLKPolarity = SPI_POLARITY_LOW;
  hspi1.Init.CLKPhase = SPI_PHASE_1EDGE;
  hspi1.Init.NSS = SPI_NSS_SOFT;
  hspi1.Init.BaudRatePrescaler = SPI_BAUDRATEPRESCALER_64;
  hspi1.Init.FirstBit = SPI_FIRSTBIT_MSB;
  hspi1.Init.TIMode = SPI_TIMODE_DISABLE;
  hspi1.Init.CRCCalculation = SPI_CRCCALCULATION_DISABLE;
  hspi1.Init.CRCPolynomial = 7;
  hspi1.Init.CRCLength = SPI_CRC_LENGTH_DATASIZE;
  hspi1.Init.NSSPMode = SPI_NSS_PULSE_ENABLE;
  if (HAL_SPI_Init(&hspi1) != HAL_OK)
  {
    Error_Handler();
  }

}

static void MX_TIM1_Init(void)
{

  TIM_ClockConfigTypeDef sClockSourceConfig = {0};
  TIM_MasterConfigTypeDef sMasterConfig = {0};
  TIM_OC_InitTypeDef sConfigOC = {0};
  TIM_BreakDeadTimeConfigTypeDef sBreakDeadTimeConfig = {0};

  htim1.Instance = TIM1;
  htim1.Init.Prescaler = 0;
  htim1.Init.CounterMode = TIM_COUNTERMODE_UP;
  htim1.Init.Period = 6799;
  htim1.Init.ClockDivision = TIM_CLOCKDIVISION_DIV1;
  htim1.Init.RepetitionCounter = 0;
  htim1.Init.AutoReloadPreload = TIM_AUTORELOAD_PRELOAD_ENABLE;
  if (HAL_TIM_Base_Init(&htim1) != HAL_OK)
  {
    Error_Handler();
  }
  sClockSourceConfig.ClockSource = TIM_CLOCKSOURCE_INTERNAL;
  if (HAL_TIM_ConfigClockSource(&htim1, &sClockSourceConfig) != HAL_OK)
  {
    Error_Handler();
  }
  if (HAL_TIM_PWM_Init(&htim1) != HAL_OK)
  {
    Error_Handler();
  }
  sMasterConfig.MasterOutputTrigger = TIM_TRGO_RESET;
  sMasterConfig.MasterOutputTrigger2 = TIM_TRGO2_RESET;
  sMasterConfig.MasterSlaveMode = TIM_MASTERSLAVEMODE_DISABLE;
  if (HAL_TIMEx_MasterConfigSynchronization(&htim1, &sMasterConfig) != HAL_OK)
  {
    Error_Handler();
  }
  sConfigOC.OCMode = TIM_OCMODE_PWM1;
  sConfigOC.Pulse = 0;
  sConfigOC.OCPolarity = TIM_OCPOLARITY_HIGH;
  sConfigOC.OCNPolarity = TIM_OCNPOLARITY_HIGH;
  sConfigOC.OCFastMode = TIM_OCFAST_DISABLE;
  sConfigOC.OCIdleState = TIM_OCIDLESTATE_RESET;
  sConfigOC.OCNIdleState = TIM_OCNIDLESTATE_RESET;
  if (HAL_TIM_PWM_ConfigChannel(&htim1, &sConfigOC, TIM_CHANNEL_1) != HAL_OK)
  {
    Error_Handler();
  }
  sBreakDeadTimeConfig.OffStateRunMode = TIM_OSSR_DISABLE;
  sBreakDeadTimeConfig.OffStateIDLEMode = TIM_OSSI_DISABLE;
  sBreakDeadTimeConfig.LockLevel = TIM_LOCKLEVEL_OFF;
  sBreakDeadTimeConfig.DeadTime = 0;
  sBreakDeadTimeConfig.BreakState = TIM_BREAK_DISABLE;
  sBreakDeadTimeConfig.BreakPolarity = TIM_BREAKPOLARITY_HIGH;
  sBreakDeadTimeConfig.BreakFilter = 0;
  sBreakDeadTimeConfig.BreakAFMode = TIM_BREAK_AFMODE_INPUT;
  sBreakDeadTimeConfig.Break2State = TIM_BREAK2_DISABLE;
  sBreakDeadTimeConfig.Break2Polarity = TIM_BREAK2POLARITY_HIGH;
  sBreakDeadTimeConfig.Break2Filter = 0;
  sBreakDeadTimeConfig.Break2AFMode = TIM_BREAK_AFMODE_INPUT;
  sBreakDeadTimeConfig.AutomaticOutput = TIM_AUTOMATICOUTPUT_DISABLE;
  if (HAL_TIMEx_ConfigBreakDeadTime(&htim1, &sBreakDeadTimeConfig) != HAL_OK)
  {
    Error_Handler();
  }
  HAL_TIM_MspPostInit(&htim1);

}

static void MX_USART2_UART_Init(void)
{

  /* USER CODE BEGIN USART2_Init 0 */
////
  /* USER CODE END USART2_Init 0 */

  /* USER CODE BEGIN USART2_Init 1 */
////
  /* USER CODE END USART2_Init 1 */
  huart2.Instance = USART2;
  huart2.Init.BaudRate = 115200;
  huart2.Init.WordLength = UART_WORDLENGTH_8B;
  huart2.Init.StopBits = UART_STOPBITS_1;
  huart2.Init.Parity = UART_PARITY_NONE;
  huart2.Init.Mode = UART_MODE_TX_RX;
  huart2.Init.HwFlowCtl = UART_HWCONTROL_NONE;
  huart2.Init.OverSampling = UART_OVERSAMPLING_16;
  huart2.Init.OneBitSampling = UART_ONE_BIT_SAMPLE_DISABLE;
  huart2.Init.ClockPrescaler = UART_PRESCALER_DIV1;
  huart2.AdvancedInit.AdvFeatureInit = UART_ADVFEATURE_NO_INIT;
  if (HAL_UART_Init(&huart2) != HAL_OK)
  {
    Error_Handler();
  }
  if (HAL_UARTEx_SetTxFifoThreshold(&huart2, UART_TXFIFO_THRESHOLD_1_8) != HAL_OK)
  {
    Error_Handler();
  }
  if (HAL_UARTEx_SetRxFifoThreshold(&huart2, UART_RXFIFO_THRESHOLD_1_8) != HAL_OK)
  {
    Error_Handler();
  }
  if (HAL_UARTEx_DisableFifoMode(&huart2) != HAL_OK)
  {
    Error_Handler();
  }
  /* USER CODE BEGIN USART2_Init 2 */
////
  /* USER CODE END USART2_Init 2 */

}

static void MX_GPIO_Init(void)
{
  GPIO_InitTypeDef GPIO_InitStruct = {0};

  /* GPIO Ports Clock Enable */
  __HAL_RCC_GPIOA_CLK_ENABLE();
  __HAL_RCC_GPIOB_CLK_ENABLE();

  /*Configure GPIO pin Output Level */
  HAL_GPIO_WritePin(GPIOA, GPIO_PIN_4, GPIO_PIN_RESET);

  /*Configure GPIO pin Output Level */
  HAL_GPIO_WritePin(LD2_GPIO_Port, LD2_Pin, GPIO_PIN_RESET);

  /*Configure GPIO pin : PA4 */
  GPIO_InitStruct.Pin = GPIO_PIN_4;
  GPIO_InitStruct.Mode = GPIO_MODE_OUTPUT_PP;
  GPIO_InitStruct.Pull = GPIO_NOPULL;
  GPIO_InitStruct.Speed = GPIO_SPEED_FREQ_LOW;
  HAL_GPIO_Init(GPIOA, &GPIO_InitStruct);

  /*Configure GPIO pin : LD2_Pin */
  GPIO_InitStruct.Pin = LD2_Pin;
  GPIO_InitStruct.Mode = GPIO_MODE_OUTPUT_PP;
  GPIO_InitStruct.Pull = GPIO_NOPULL;
  GPIO_InitStruct.Speed = GPIO_SPEED_FREQ_LOW;
  HAL_GPIO_Init(LD2_GPIO_Port, &GPIO_InitStruct);

}

void Error_Handler(void)
{
  __disable_irq();
  while (1)
  {
  }
}
